VERSION 5.7 ;
UNITS
  DATABASE MICRONS 1000 ;
END UNITS

LAYER nwell
  TYPE MASTERSLICE ;
END nwell

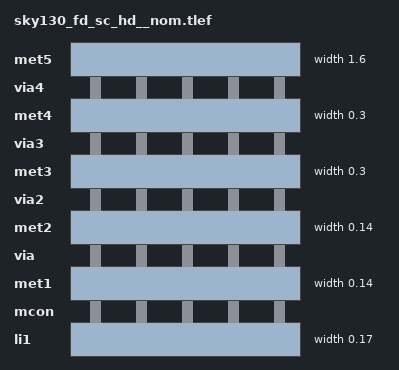
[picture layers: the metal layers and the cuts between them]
LAYER li1
  TYPE ROUTING ;
  WIDTH 0.17 ;
  RESISTANCE RPERSQ 0.1250 ;
  CAPACITANCE CPERSQDIST 2.500e-05 ;
  EDGECAPACITANCE 3.700e-05 ;
END li1

LAYER mcon
  TYPE CUT ;
  RESISTANCE 9.3 ;
END mcon

LAYER met1
  TYPE ROUTING ;
  WIDTH 0.14 ;
  RESISTANCE RPERSQ 0.1050 ;
  CAPACITANCE CPERSQDIST 2.300e-05 ;
  EDGECAPACITANCE 3.500e-05 ;
END met1

LAYER via
  TYPE CUT ;
  RESISTANCE 7.800000000000001 ;
END via

LAYER met2
  TYPE ROUTING ;
  WIDTH 0.14 ;
  RESISTANCE RPERSQ 0.0850 ;
  CAPACITANCE CPERSQDIST 2.100e-05 ;
  EDGECAPACITANCE 3.300e-05 ;
END met2

LAYER via2
  TYPE CUT ;
  RESISTANCE 6.300000000000001 ;
END via2

LAYER met3
  TYPE ROUTING ;
  WIDTH 0.3 ;
  RESISTANCE RPERSQ 0.0650 ;
  CAPACITANCE CPERSQDIST 1.900e-05 ;
  EDGECAPACITANCE 3.100e-05 ;
END met3

LAYER via3
  TYPE CUT ;
  RESISTANCE 4.800000000000001 ;
END via3

LAYER met4
  TYPE ROUTING ;
  WIDTH 0.3 ;
  RESISTANCE RPERSQ 0.0450 ;
  CAPACITANCE CPERSQDIST 1.700e-05 ;
  EDGECAPACITANCE 2.900e-05 ;
END met4

LAYER via4
  TYPE CUT ;
  RESISTANCE 3.3000000000000007 ;
END via4

LAYER met5
  TYPE ROUTING ;
  WIDTH 1.6 ;
  RESISTANCE RPERSQ 0.0250 ;
  CAPACITANCE CPERSQDIST 1.500e-05 ;
  EDGECAPACITANCE 2.700e-05 ;
END met5
END LIBRARY
